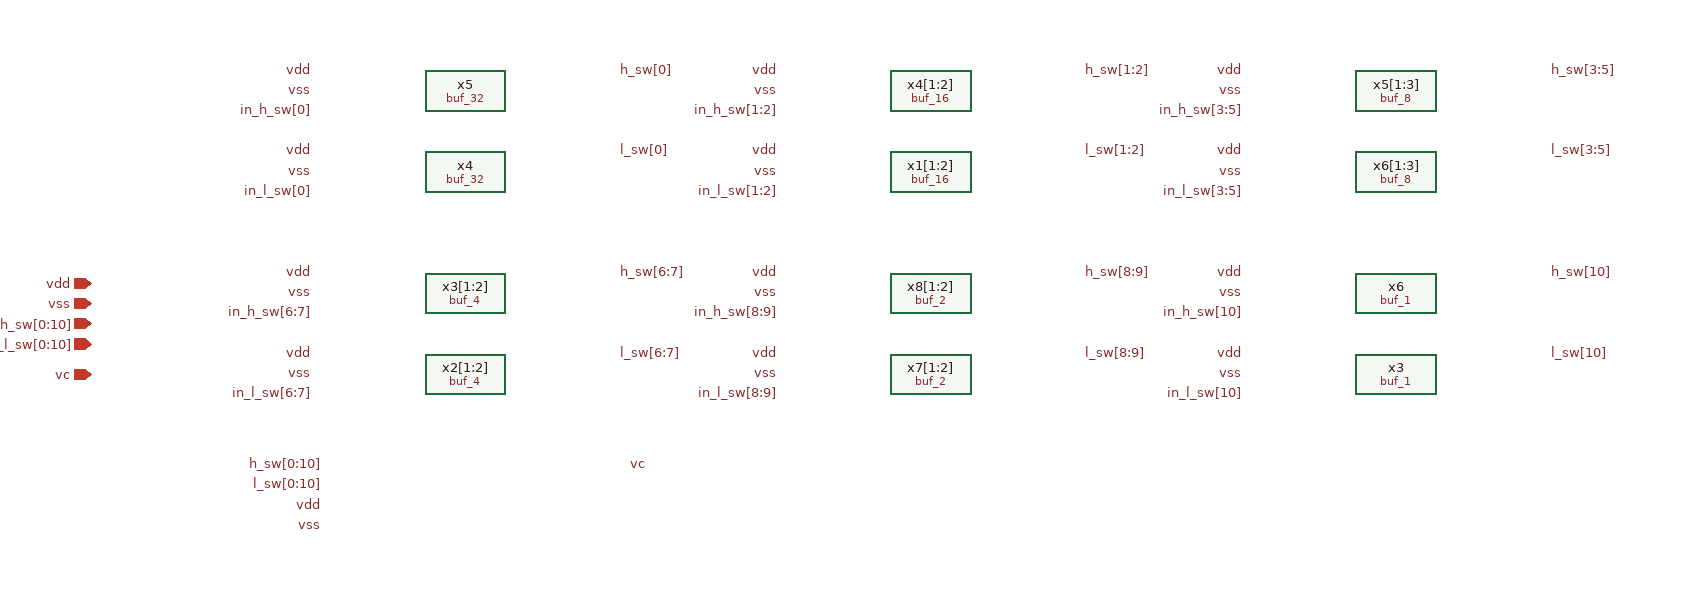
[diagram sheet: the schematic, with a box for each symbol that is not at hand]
v {xschem version=3.4.8RC file_version=1.3}
G {}
K {}
V {}
S {}
F {}
E {}
C {lab_wire.sym} 330 -120 0 0 {name=p1 lab=h_sw[0:10]}
C {lab_wire.sym} 330 -100 0 0 {name=p2 lab=l_sw[0:10]}
C {lab_wire.sym} 630 -120 0 1 {name=p3 lab=vc}
C {lab_wire.sym} 330 -60 0 0 {name=p4 lab=vss}
C {ipin.sym} 100 -300 0 0 {name=p37 lab=vdd}
C {ipin.sym} 100 -280 0 0 {name=p38 lab=vss}
C {ipin.sym} 100 -260 0 0 {name=p39 lab=in_h_sw[0:10]}
C {ipin.sym} 100 -240 0 0 {name=p40 lab=in_l_sw[0:10]}
C {iopin.sym} 100 -210 0 0 {name=p41 lab=vc}
C {buf_1.sym} 1390 -210 0 0 {name=x3}
C {buf_2.sym} 930 -210 0 0 {name=x7[1:2]}
C {buf_4.sym} 470 -210 0 0 {name=x2[1:2]}
C {buf_8.sym} 1390 -410 0 0 {name=x6[1:3]}
C {buf_1.sym} 1390 -290 0 0 {name=x6}
C {buf_2.sym} 930 -290 0 0 {name=x8[1:2]}
C {buf_4.sym} 470 -290 0 0 {name=x3[1:2]}
C {buf_8.sym} 1390 -490 0 0 {name=x5[1:3]}
C {lab_wire.sym} 1240 -230 0 0 {name=p42 lab=vdd}
C {lab_wire.sym} 1240 -210 0 0 {name=p43 lab=vss}
C {lab_wire.sym} 780 -230 0 0 {name=p44 lab=vdd}
C {lab_wire.sym} 780 -210 0 0 {name=p45 lab=vss}
C {lab_wire.sym} 320 -230 0 0 {name=p46 lab=vdd}
C {lab_wire.sym} 320 -210 0 0 {name=p47 lab=vss}
C {lab_wire.sym} 1240 -430 0 0 {name=p48 lab=vdd}
C {lab_wire.sym} 1240 -410 0 0 {name=p49 lab=vss}
C {lab_wire.sym} 1240 -310 0 0 {name=p50 lab=vdd}
C {lab_wire.sym} 1240 -290 0 0 {name=p51 lab=vss}
C {lab_wire.sym} 780 -310 0 0 {name=p52 lab=vdd}
C {lab_wire.sym} 780 -290 0 0 {name=p53 lab=vss}
C {lab_wire.sym} 320 -310 0 0 {name=p54 lab=vdd}
C {lab_wire.sym} 320 -290 0 0 {name=p55 lab=vss}
C {lab_wire.sym} 1240 -510 0 0 {name=p56 lab=vdd}
C {lab_wire.sym} 1240 -490 0 0 {name=p57 lab=vss}
C {lab_wire.sym} 1540 -510 0 1 {name=p58 lab=h_sw[3:5]}
C {lab_wire.sym} 1540 -430 0 1 {name=p59 lab=l_sw[3:5]}
C {lab_wire.sym} 620 -310 0 1 {name=p60 lab=h_sw[6:7]}
C {lab_wire.sym} 620 -230 0 1 {name=p61 lab=l_sw[6:7]}
C {lab_wire.sym} 1080 -310 0 1 {name=p62 lab=h_sw[8:9]}
C {lab_wire.sym} 1080 -230 0 1 {name=p63 lab=l_sw[8:9]}
C {lab_wire.sym} 1540 -310 0 1 {name=p64 lab=h_sw[10]}
C {lab_wire.sym} 1540 -230 0 1 {name=p65 lab=l_sw[10]}
C {lab_wire.sym} 1240 -270 0 0 {name=p66 lab=in_h_sw[10]}
C {lab_wire.sym} 780 -270 0 0 {name=p67 lab=in_h_sw[8:9]}
C {lab_wire.sym} 320 -270 0 0 {name=p68 lab=in_h_sw[6:7]}
C {lab_wire.sym} 1240 -470 0 0 {name=p69 lab=in_h_sw[3:5]}
C {lab_wire.sym} 1240 -390 0 0 {name=p70 lab=in_l_sw[3:5]}
C {lab_wire.sym} 320 -190 0 0 {name=p71 lab=in_l_sw[6:7]}
C {lab_wire.sym} 780 -190 0 0 {name=p72 lab=in_l_sw[8:9]}
C {lab_wire.sym} 1240 -190 0 0 {name=p73 lab=in_l_sw[10]}
C {lab_wire.sym} 330 -80 0 0 {name=p5 lab=vdd}
C {buf_16.sym} 930 -410 0 0 {name=x1[1:2]}
C {buf_16.sym} 930 -490 0 0 {name=x4[1:2]}
C {lab_wire.sym} 780 -430 0 0 {name=p6 lab=vdd}
C {lab_wire.sym} 780 -410 0 0 {name=p7 lab=vss}
C {lab_wire.sym} 780 -510 0 0 {name=p9 lab=vdd}
C {lab_wire.sym} 780 -490 0 0 {name=p10 lab=vss}
C {buf_32.sym} 470 -410 0 0 {name=x4}
C {buf_32.sym} 470 -490 0 0 {name=x5}
C {lab_wire.sym} 320 -430 0 0 {name=p8 lab=vdd}
C {lab_wire.sym} 320 -410 0 0 {name=p12 lab=vss}
C {lab_wire.sym} 320 -510 0 0 {name=p13 lab=vdd}
C {lab_wire.sym} 320 -490 0 0 {name=p14 lab=vss}
C {lab_wire.sym} 620 -510 0 1 {name=p15 lab=h_sw[0]}
C {lab_wire.sym} 620 -430 0 1 {name=p16 lab=l_sw[0]}
C {lab_wire.sym} 320 -470 0 0 {name=p17 lab=in_h_sw[0]}
C {lab_wire.sym} 320 -390 0 0 {name=p18 lab=in_l_sw[0]}
C {lab_wire.sym} 1080 -510 0 1 {name=p11 lab=h_sw[1:2]}
C {lab_wire.sym} 1080 -430 0 1 {name=p19 lab=l_sw[1:2]}
C {lab_wire.sym} 780 -470 0 0 {name=p20 lab=in_h_sw[1:2]}
C {lab_wire.sym} 780 -390 0 0 {name=p21 lab=in_l_sw[1:2]}
